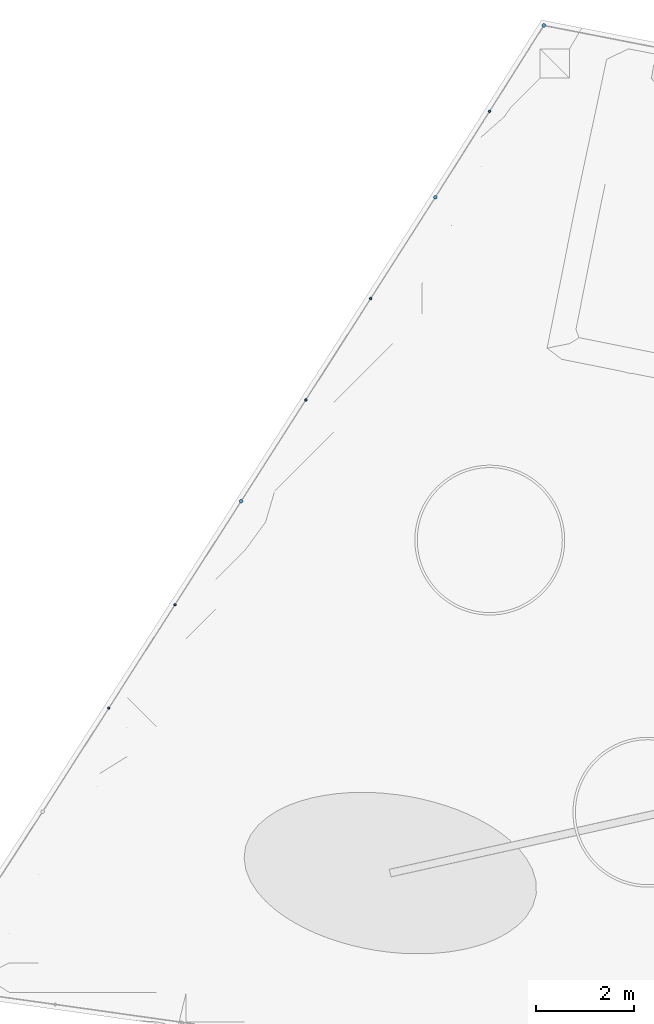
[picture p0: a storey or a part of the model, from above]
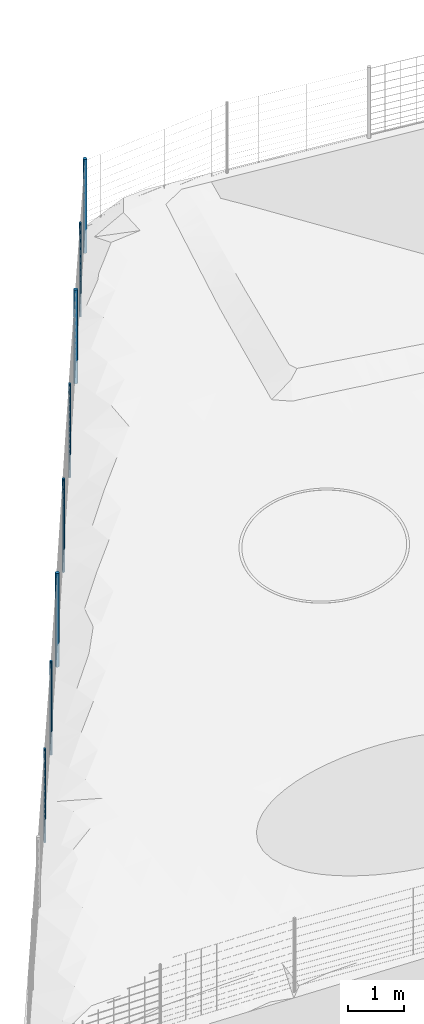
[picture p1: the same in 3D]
Properties of the parts of a building model (IFC4), part 3 of 3

# IfcPlate (158)
Name | In | PredefinedType | Material | Note | Product | NominalThickness_m | ModelledThickness_m | Status
Cobertura 7.16 | 01 · Jardim de inverno | SHEET | Policarbonato alveolar 16 mm · translúcido | 8 mm nominal glass; safety glazing and panel subdivision require specification. | Multiwall polycarbonate | 0.016 | 0.008 | Thickness, supplier and fixing system to confirm
Cobertura 8.16 | 01 · Jardim de inverno | SHEET | Policarbonato alveolar 16 mm · translúcido | 8 mm nominal glass; safety glazing and panel subdivision require specification. | Multiwall polycarbonate | 0.016 | 0.008 | Thickness, supplier and fixing system to confirm
Cobertura 1.17 | 01 · Jardim de inverno | SHEET | Policarbonato alveolar 16 mm · translúcido | 8 mm nominal glass; safety glazing and panel subdivision require specification. | Multiwall polycarbonate | 0.016 | 0.008 | Thickness, supplier and fixing system to confirm
Cobertura 2.17 | 01 · Jardim de inverno | SHEET | Policarbonato alveolar 16 mm · translúcido | 8 mm nominal glass; safety glazing and panel subdivision require specification. | Multiwall polycarbonate | 0.016 | 0.008 | Thickness, supplier and fixing system to confirm
Cobertura 3.17 | 01 · Jardim de inverno | SHEET | Policarbonato alveolar 16 mm · translúcido | 8 mm nominal glass; safety glazing and panel subdivision require specification. | Multiwall polycarbonate | 0.016 | 0.008 | Thickness, supplier and fixing system to confirm
Cobertura 4.17 | 01 · Jardim de inverno | SHEET | Policarbonato alveolar 16 mm · translúcido | 8 mm nominal glass; safety glazing and panel subdivision require specification. | Multiwall polycarbonate | 0.016 | 0.008 | Thickness, supplier and fixing system to confirm
Cobertura 5.17 | 01 · Jardim de inverno | SHEET | Policarbonato alveolar 16 mm · translúcido | 8 mm nominal glass; safety glazing and panel subdivision require specification. | Multiwall polycarbonate | 0.016 | 0.008 | Thickness, supplier and fixing system to confirm
Cobertura 6.17 | 01 · Jardim de inverno | SHEET | Policarbonato alveolar 16 mm · translúcido | 8 mm nominal glass; safety glazing and panel subdivision require specification. | Multiwall polycarbonate | 0.016 | 0.008 | Thickness, supplier and fixing system to confirm
Cobertura 7.17 | 01 · Jardim de inverno | SHEET | Policarbonato alveolar 16 mm · translúcido | 8 mm nominal glass; safety glazing and panel subdivision require specification. | Multiwall polycarbonate | 0.016 | 0.008 | Thickness, supplier and fixing system to confirm
Cobertura 8.17 | 01 · Jardim de inverno | SHEET | Policarbonato alveolar 16 mm · translúcido | 8 mm nominal glass; safety glazing and panel subdivision require specification. | Multiwall polycarbonate | 0.016 | 0.008 | Thickness, supplier and fixing system to confirm
2 x Empena da estufa | 01 · Jardim de inverno |  | Policarbonato alveolar 16 mm · translúcido |  | Multiwall polycarbonate | 0.016 | 0.008 | Thickness, supplier and fixing system to confirm
Cisterna · tampa estanque de inspeção | 00 · Habitação e estacionamento | SHEET | Aço galvanizado / Stahl verzinkt | Flush, closed 900 mm maintenance hatch; cover capacity and safe maintenance access to detail. Not a routine entrance.
4 x Pérgola · chapa de ancoragem | 00 · Habitação e estacionamento | SHEET | Aço galvanizado / Stahl verzinkt
9 x Projeção estufa · chapa de ancoragem | 00 · Habitação e estacionamento | SHEET | Aço galvanizado / Stahl verzinkt
2 x Contentor · chapa lateral | 00 · Habitação e estacionamento |  | Contentor · pintura 1
Contentor · chapa de fundo | 00 · Habitação e estacionamento |  | Contentor · pintura 1
2 x Contentor · chapa lateral | 00 · Habitação e estacionamento |  | Contentor · pintura 2
Contentor · chapa de fundo | 00 · Habitação e estacionamento |  | Contentor · pintura 2

# IfcRailing (23)
PredefinedType: GUARDRAIL; Material: Aço pintado / Stahl lackiert
Pset_CasaProvenance - DesignSource: Casa Sobreposta / configuration.json; ReferenceFile: 260617_CasaDFL_Estrutura_Terreno.ifc; ConstructionBasis: DESIGN_ASSUMPTION; Note: Study guard 1.10 m; twin handrails at 0.70 and 0.90 m on ramp; loads and fixings unverified.
Name | In
5 x Guarda perimetral da estufa | 01 · Jardim de inverno
Corrimão sala | 00 · Habitação e estacionamento
Corrimão garagem | 00 · Habitação e estacionamento
5 x Guarda do vazio | 01 · Jardim de inverno
Pódio · guarda sul | 00 · Habitação e estacionamento
Pódio · guarda poente sul | 00 · Habitação e estacionamento
Pódio · guarda poente norte | 00 · Habitação e estacionamento
Pódio · guarda norte | 00 · Habitação e estacionamento
2 x Jardim · corrimão poente | 00 · Habitação e estacionamento
2 x Jardim · guarda do patamar | 00 · Habitação e estacionamento
3 x Varanda · guarda | 00 · Habitação e estacionamento

# IfcRailing: SHEEP_WIRE_FENCE (82)
In: Lares · Rua das Mercês · artigo 4771
PredefinedType: USERDEFINED; Material: Aço galvanizado / Stahl verzinkt
Pset_CasaProvenance - DesignSource: Casa Sobreposta / configuration.json; ReferenceFile: 260617_CasaDFL_Estrutura_Terreno.ifc; ConstructionBasis: DESIGN_ASSUMPTION; Note: R10 concept geometry; dimensions and connections not structurally verified.
Pset_CasaFence - Height_m: 1.5; Mesh: Galvanised sheep netting, graduated line wires, 0.30 m vertical stays; Status: CONCEPT; wire gauge, tensioning and posts to specify
Name | PostSpacing_m
Vedação · rede ovelheira 1.001 | 2.31221
Vedação · rede ovelheira 1.002 | 2.31221
Vedação · rede ovelheira 1.003 | 2.31221
Vedação · rede ovelheira 1.004 | 2.85062
Vedação · rede ovelheira 1.005 | 2.85062
Vedação · rede ovelheira 1.006 | 2.85062
Vedação · rede ovelheira 1.007 | 2.85062
Vedação · rede ovelheira 1.008 | 2.41772
Vedação · rede ovelheira 1.009 | 2.41772
Vedação · rede ovelheira 1.010 | 2.41772
Vedação · rede ovelheira 1.011 | 2.41772
Vedação · rede ovelheira 1.012 | 2.41772
Vedação · rede ovelheira 1.013 | 2.4459
Vedação · rede ovelheira 1.014 | 2.4459
Vedação · rede ovelheira 1.015 | 2.4459
Vedação · rede ovelheira 1.016 | 2.4459
Vedação · rede ovelheira 1.017 | 2.4459
Vedação · rede ovelheira 1.018 | 2.41457
Vedação · rede ovelheira 1.019 | 2.41457
Vedação · rede ovelheira 1.020 | 2.41457
Vedação · rede ovelheira 1.021 | 2.41457
Vedação · rede ovelheira 1.022 | 2.41457
Vedação · rede ovelheira 1.023 | 2.93474
Vedação · rede ovelheira 1.024 | 2.93474
Vedação · rede ovelheira 1.025 | 2.93474
Vedação · rede ovelheira 1.026 | 2.93474
Vedação · rede ovelheira 1.027 | 2.4949
Vedação · rede ovelheira 1.028 | 2.4949
Vedação · rede ovelheira 1.029 | 2.4949
Vedação · rede ovelheira 1.030 | 2.4949
Vedação · rede ovelheira 1.031 | 2.4949
Vedação · rede ovelheira 1.032 | 2.41477
Vedação · rede ovelheira 1.033 | 2.41477
Vedação · rede ovelheira 1.034 | 2.41477
Vedação · rede ovelheira 1.035 | 2.41477
Vedação · rede ovelheira 1.036 | 2.90303
Vedação · rede ovelheira 1.037 | 2.90303
Vedação · rede ovelheira 1.038 | 2.59069
Vedação · rede ovelheira 1.039 | 2.59069
Vedação · rede ovelheira 1.040 | 2.59069
Vedação · rede ovelheira 1.041 | 2.12292
Vedação · rede ovelheira 1.042 | 2.12292
Vedação · rede ovelheira 1.043 | 2.49871
Vedação · rede ovelheira 1.044 | 2.49871
Vedação · rede ovelheira 1.045 | 2.49871
Vedação · rede ovelheira 1.046 | 2.44661
Vedação · rede ovelheira 1.047 | 2.44661
Vedação · rede ovelheira 1.048 | 2.44661
Vedação · rede ovelheira 1.049 | 2.06726
Vedação · rede ovelheira 1.050 | 2.06726
Vedação · rede ovelheira 1.051 | 2.68804
Vedação · rede ovelheira 1.052 | 2.68804
Vedação · rede ovelheira 1.053 | 2.76823
Vedação · rede ovelheira 1.054 | 2.76823
Vedação · rede ovelheira 1.055 | 2.76823
Vedação · rede ovelheira 1.056 | 2.73364
Vedação · rede ovelheira 1.057 | 2.73364
Vedação · rede ovelheira 1.058 | 2.73364
Vedação · rede ovelheira 1.059 | 2.9388
Vedação · rede ovelheira 1.060 | 2.9388
Vedação · rede ovelheira 1.061 | 2.99875
Vedação · rede ovelheira 1.062 | 2.99875
Vedação · rede ovelheira 1.063 | 2.99875
Vedação · rede ovelheira 1.064 | 2.42137
Vedação · rede ovelheira 1.065 | 2.42137
Vedação · rede ovelheira 1.066 | 2.42137
Vedação · rede ovelheira 1.067 | 2.42137
Vedação · rede ovelheira 1.068 | 2.65677
Vedação · rede ovelheira 1.069 | 2.65677
Vedação · rede ovelheira 1.070 | 2.65677
Vedação · rede ovelheira 1.071 | 2.65677
Vedação · rede ovelheira 1.072 | 2.96086
Vedação · rede ovelheira 1.073 | 2.96086
Vedação · rede ovelheira 1.074 | 2.96086
Vedação · rede ovelheira 1.075 | 2.83036
Vedação · rede ovelheira 1.076 | 2.83036
Vedação · rede ovelheira 1.077 | 2.83036
Vedação · rede ovelheira 1.078 | 2.61662
Vedação · rede ovelheira 1.079 | 2.61662
Vedação · rede ovelheira 1.080 | 2.61662
Vedação · rede ovelheira 1.081 | 2.61662
Vedação · rede ovelheira 1.082 | 1.96455

# IfcRoof, Cobertura translúcida da estufa
In: 01 · Jardim de inverno
PredefinedType: BARREL_ROOF; Material: Policarbonato alveolar 16 mm · translúcido
Pset_CasaProvenance - DesignSource: Casa Sobreposta / configuration.json; ReferenceFile: 260617_CasaDFL_Estrutura_Terreno.ifc; ConstructionBasis: DESIGN_ASSUMPTION; Note: Configurator Coutras section, scaled to 7.90 m with raised ridge; 8 mm glass and 35 mm ribs are study assumptions.
Pset_CasaPolycarbonate - Product: Multiwall polycarbonate; NominalThickness_m: 0.016; ModelledThickness_m: 0.008; Status: Thickness, supplier and fixing system to confirm

# IfcSanitaryTerminal (8)
Material: Cerâmica sanitária — esquema
Pset_CasaProvenance - DesignSource: Casa Sobreposta / configuration.json; ReferenceFile: 260617_CasaDFL_Estrutura_Terreno.ifc; ConstructionBasis: DESIGN_ASSUMPTION
Name | In | PredefinedType | Note
Banheira | 00 · Habitação e estacionamento | BATH | Schematic fixture, not a manufacturer object.
Lavatório 1 | 00 · Habitação e estacionamento | WASHHANDBASIN | Schematic fixture, not a manufacturer object.
Lavatório 2 | 00 · Habitação e estacionamento | WASHHANDBASIN | Schematic fixture, not a manufacturer object.
Sanita | 00 · Habitação e estacionamento | TOILETPAN | Schematic fixture, not a manufacturer object.
Bancada de cozinha | 00 · Habitação e estacionamento | TOILETPAN | Schematic fixture, not a manufacturer object.
Lavatório superior | 01 · Jardim de inverno | WASHHANDBASIN
Sanita superior | 01 · Jardim de inverno | TOILETPAN
Duche superior | 01 · Jardim de inverno | SHOWER

# IfcSlab (11)
Pset_CasaProvenance - DesignSource: Casa Sobreposta / configuration.json; ReferenceFile: 260617_CasaDFL_Estrutura_Terreno.ifc
Name | In | PredefinedType | Material | ConstructionBasis
OSB estrutural · 20 mm | 01 · Jardim de inverno | FLOOR | OSB | ADAPTED_REFERENCE | Pset_CasaProvenance - Note: Two real stair voids. Light protective finish assumed; drains and waterproof upstands require detailing.
Cisterna · laje de fundo 200 mm | -01 · Cisterna sob o terraço | BASESLAB | Betão armado / Stahlbeton | DESIGN_ASSUMPTION
Pódio · laje da casa 250 mm | 00 · Habitação e estacionamento | FLOOR | Betão armado / Stahlbeton | DESIGN_ASSUMPTION | Pset_CasaProvenance - Note: Suspended slab on discrete piers and grade beams. Natural slope retained where clear; local shallow excavation where beams meet rising ground. Sizes unverified.
Pódio · terraço e faixa de proteção sul | 00 · Habitação e estacionamento | FLOOR | Betão armado / Stahlbeton | DESIGN_ASSUMPTION | Pset_CasaProvenance - Note: Terrace 40 mm below house. West terrace over void/cistern; shallow local formation to east. Parking is a separate ground-supported pavement.
Estacionamento · pavimento apoiado no solo | 00 · Habitação e estacionamento | BASESLAB | Betão armado / Stahlbeton | DESIGN_ASSUMPTION | Pset_CasaProvenance - Note: R10 concept geometry; dimensions and connections not structurally verified.; Pset_CasaParking - GroundSupported: yes; LongitudinalGrade_percent: 2.5; Crossfall_percent: 4; HouseThresholdStep_m: 0.02; Status: Concept grading; pavement build-up and accessibility to detail
Jardim · patamar poente | 00 · Habitação e estacionamento | LANDING | Betão armado / Stahlbeton | DESIGN_ASSUMPTION
Varanda · faixa poente 1,20 m úteis | 01 · Jardim de inverno | FLOOR | Aço galvanizado / Stahl verzinkt | DESIGN_ASSUMPTION | Pset_CasaProvenance - Note: Open upper gallery; non-slip deck and member connections to design. 1.25 m gross strip, approximately 1.20 m clear.
2 x Contentor · piso ou teto | 00 · Habitação e estacionamento | FLOOR | Contentor · pintura 1 | DESIGN_ASSUMPTION
2 x Contentor · piso ou teto | 00 · Habitação e estacionamento | FLOOR | Contentor · pintura 2 | DESIGN_ASSUMPTION

# IfcStair (3)
In: 00 · Habitação e estacionamento
PredefinedType: STRAIGHT_RUN_STAIR
Pset_CasaProvenance - DesignSource: Casa Sobreposta / configuration.json; ReferenceFile: 260617_CasaDFL_Estrutura_Terreno.ifc
Name | ConstructionBasis | Note
Escada sala | ADAPTED_REFERENCE | Configurator 18 x 0.18 m risers / 17 x 0.265 m goings / 0.70 m width. Steel channels and OSB treads adapted from source.
Escada garagem | ADAPTED_REFERENCE | Configurator 18 x 0.18 m risers / 17 x 0.265 m goings / 0.70 m width. Steel channels and OSB treads adapted from source.
Jardim · escada pela fachada poente | DESIGN_ASSUMPTION | West-facing descent; no south opening. Survey-based concept.

# IfcStairFlight (3)
In: 00 · Habitação e estacionamento
PredefinedType: STRAIGHT
Pset_CasaProvenance - DesignSource: Casa Sobreposta / configuration.json; ReferenceFile: 260617_CasaDFL_Estrutura_Terreno.ifc
Name | NumberOfRisers | NumberOfTreads | RiserHeight (m) | TreadLength (m) | Material | ConstructionBasis
Lanço sala | 18 | 17 | 0.18 | 0.265 | OSB | ADAPTED_REFERENCE
Lanço garagem | 18 | 17 | 0.18 | 0.265 | OSB | ADAPTED_REFERENCE
Jardim · lanço poente | 12 | 11 | 0.159167 | 0.3 | Betão armado / Stahlbeton | DESIGN_ASSUMPTION

# IfcTank: RAINWATER_CISTERN, Cisterna · reservatório pluvial de estudo
In: -01 · Cisterna sob o terraço
PredefinedType: STORAGE
Pset_CasaProvenance - DesignSource: Casa Sobreposta / configuration.json; ReferenceFile: 260617_CasaDFL_Estrutura_Terreno.ifc; ConstructionBasis: DESIGN_ASSUMPTION; Note: Composite concrete vessel; provisional geometry only. No ordinary occupancy or stair access. Water depth and capacity to design.
Pset_CasaCistern - InternalPlanArea_m2: 17.8125; WaterDepthAssumed_m: 2; GeometricWaterVolume_m3: 35.625; SoffitClearanceAboveWater_m: 0.31; Status: Provisional water envelope; hydrostatic, uplift, watertightness, filtration, overflow and maintenance design pending

# IfcWall (17)
Pset_CasaProvenance - DesignSource: Casa Sobreposta / configuration.json; ReferenceFile: 260617_CasaDFL_Estrutura_Terreno.ifc; ConstructionBasis: ADAPTED_REFERENCE
Name | In | Material | OverallThickness_m | SourceModelSkinThicknesses_m | Core_m | Pset_CasaAssembly, Note
Divisória 1 · OSB 22 mm nas duas faces | 00 · Habitação e estacionamento | OSB, Lã mineral / Mineralwolle 2 | Pset_CasaProvenance - Note: Original centreline/door positions preserved; schematic footprint widened 20 mm per side. 22 mm OSB linings; mineral wool core; stud layout not developed.
Divisória 2 · OSB 22 mm nas duas faces | 00 · Habitação e estacionamento | OSB, Lã mineral / Mineralwolle 2 | Pset_CasaProvenance - Note: Original centreline/door positions preserved; schematic footprint widened 20 mm per side. 22 mm OSB linings; mineral wool core; stud layout not developed.
Divisória 3 · OSB 22 mm nas duas faces | 00 · Habitação e estacionamento | OSB, Lã mineral / Mineralwolle 2 | Pset_CasaProvenance - Note: Original centreline/door positions preserved; schematic footprint widened 20 mm per side. 22 mm OSB linings; mineral wool core; stud layout not developed.
Divisória 4 · OSB 22 mm nas duas faces | 00 · Habitação e estacionamento | OSB, Lã mineral / Mineralwolle 2 | Pset_CasaProvenance - Note: Original centreline/door positions preserved; schematic footprint widened 20 mm per side. 22 mm OSB linings; mineral wool core; stud layout not developed.
Fachada norte · sandwich Casa DFL | 00 · Habitação e estacionamento | Aço pintado / Stahl lackiert 0.005 m, Lã mineral / Mineralwolle 2 0.12 m, Aço pintado / Stahl lackiert 0.00516 m | 0.13016 | 0.005 / 0.00516 | 0.12 | Source geometry retained; commercial sheet specification not established.
Separação do estacionamento | 00 · Habitação e estacionamento | Aço pintado / Stahl lackiert 0.005 m, Lã mineral / Mineralwolle 2 0.12 m, Aço pintado / Stahl lackiert 0.00516 m | 0.13016 | 0.005 / 0.00516 | 0.12 | Source geometry retained; commercial sheet specification not established.
Painel opaco sul 0 | 00 · Habitação e estacionamento | Aço pintado / Stahl lackiert 0.005 m, Lã mineral / Mineralwolle 2 0.12 m, Aço pintado / Stahl lackiert 0.00516 m | 0.13016 | 0.005 / 0.00516 | 0.12 | Source geometry retained; commercial sheet specification not established.
Painel opaco sul 1 | 00 · Habitação e estacionamento | Aço pintado / Stahl lackiert 0.005 m, Lã mineral / Mineralwolle 2 0.12 m, Aço pintado / Stahl lackiert 0.00516 m | 0.13016 | 0.005 / 0.00516 | 0.12 | Source geometry retained; commercial sheet specification not established.
Painel opaco sul 3 | 00 · Habitação e estacionamento | Aço pintado / Stahl lackiert 0.005 m, Lã mineral / Mineralwolle 2 0.12 m, Aço pintado / Stahl lackiert 0.00516 m | 0.13016 | 0.005 / 0.00516 | 0.12 | Source geometry retained; commercial sheet specification not established.
Painel opaco sul 5 | 00 · Habitação e estacionamento | Aço pintado / Stahl lackiert 0.005 m, Lã mineral / Mineralwolle 2 0.12 m, Aço pintado / Stahl lackiert 0.00516 m | 0.13016 | 0.005 / 0.00516 | 0.12 | Source geometry retained; commercial sheet specification not established.
Painel opaco sul 7 | 00 · Habitação e estacionamento | Aço pintado / Stahl lackiert 0.005 m, Lã mineral / Mineralwolle 2 0.12 m, Aço pintado / Stahl lackiert 0.00516 m | 0.13016 | 0.005 / 0.00516 | 0.12 | Source geometry retained; commercial sheet specification not established.
Painel opaco sul 9 | 00 · Habitação e estacionamento | Aço pintado / Stahl lackiert 0.005 m, Lã mineral / Mineralwolle 2 0.12 m, Aço pintado / Stahl lackiert 0.00516 m | 0.13016 | 0.005 / 0.00516 | 0.12 | Source geometry retained; commercial sheet specification not established.
Painel opaco sul 11 | 00 · Habitação e estacionamento | Aço pintado / Stahl lackiert 0.005 m, Lã mineral / Mineralwolle 2 0.12 m, Aço pintado / Stahl lackiert 0.00516 m | 0.13016 | 0.005 / 0.00516 | 0.12 | Source geometry retained; commercial sheet specification not established.
Banho superior · poente | 01 · Jardim de inverno | OSB
Banho superior · norte | 01 · Jardim de inverno | OSB
Banho superior · nascente | 01 · Jardim de inverno | OSB
Banho superior · sul | 01 · Jardim de inverno | OSB

# IfcWall: Cisterna · parede nascente
In: -01 · Cisterna sob o terraço
PredefinedType: USERDEFINED; Material: Betão armado / Stahlbeton
Pset_CasaProvenance - DesignSource: Casa Sobreposta / configuration.json; ReferenceFile: 260617_CasaDFL_Estrutura_Terreno.ifc; ConstructionBasis: DESIGN_ASSUMPTION; Note: 250 mm RC study wall, waterproofing and joints to detail; no retaining capacity asserted.

# IfcWall: Cisterna · parede norte
In: -01 · Cisterna sob o terraço
PredefinedType: USERDEFINED; Material: Betão armado / Stahlbeton
Pset_CasaProvenance - DesignSource: Casa Sobreposta / configuration.json; ReferenceFile: 260617_CasaDFL_Estrutura_Terreno.ifc; ConstructionBasis: DESIGN_ASSUMPTION; Note: 250 mm RC study wall, waterproofing and joints to detail; no retaining capacity asserted.

# IfcWall: Cisterna · parede poente
In: -01 · Cisterna sob o terraço
PredefinedType: USERDEFINED; Material: Betão armado / Stahlbeton
Pset_CasaProvenance - DesignSource: Casa Sobreposta / configuration.json; ReferenceFile: 260617_CasaDFL_Estrutura_Terreno.ifc; ConstructionBasis: DESIGN_ASSUMPTION; Note: 250 mm RC study wall, waterproofing and joints to detail; no retaining capacity asserted.

# IfcWall: Cisterna · parede sul
In: -01 · Cisterna sob o terraço
PredefinedType: USERDEFINED; Material: Betão armado / Stahlbeton
Pset_CasaProvenance - DesignSource: Casa Sobreposta / configuration.json; ReferenceFile: 260617_CasaDFL_Estrutura_Terreno.ifc; ConstructionBasis: DESIGN_ASSUMPTION; Note: 250 mm RC study wall, waterproofing and joints to detail; no retaining capacity asserted.

# IfcWindow (58)
PredefinedType: WINDOW; PartitioningType: SINGLE_PANEL
Pset_CasaProvenance - DesignSource: Casa Sobreposta / configuration.json; ReferenceFile: 260617_CasaDFL_Estrutura_Terreno.ifc; ConstructionBasis: DESIGN_ASSUMPTION
Name | In | OverallHeight (m) | OverallWidth (m) | Material | Product | NominalThickness_m | ModelledThickness_m | Status
Rasgo norte 1 | 00 · Habitação e estacionamento | 0.3 | 3.79 | Vidro / Normalglas
Rasgo norte 2 | 00 · Habitação e estacionamento | 0.3 | 3.79 | Vidro / Normalglas
Rasgo norte 3 | 00 · Habitação e estacionamento | 0.3 | 3.79 | Vidro / Normalglas
Rasgo norte 4 | 00 · Habitação e estacionamento | 0.3 | 3.79 | Vidro / Normalglas
Rasgo norte 5 | 00 · Habitação e estacionamento | 0.3 | 3.79 | Vidro / Normalglas
Rasgo norte 6 | 00 · Habitação e estacionamento | 0.3 | 3.79 | Vidro / Normalglas
Rasgo norte 7 | 00 · Habitação e estacionamento | 0.3 | 0.71 | Vidro / Normalglas
Fachada poente integralmente envidraçada · módulo 1 | 00 · Habitação e estacionamento | 2.918 | 1.55 | Vidro / Normalglas | Pset_CasaGlazedFacade - Revision: R02 · kiwi pergola; Facade: WEST / highlighted end in user sketch; Infill: Full-height glazing; no opaque infill; GlazingSpecification: 8 mm nominal representation only; insulated safety glazing assembly to specify
Fachada poente integralmente envidraçada · módulo 2 | 00 · Habitação e estacionamento | 2.918 | 1.55 | Vidro / Normalglas | Pset_CasaGlazedFacade - Revision: R02 · kiwi pergola; Facade: WEST / highlighted end in user sketch; Infill: Full-height glazing; no opaque infill; GlazingSpecification: 8 mm nominal representation only; insulated safety glazing assembly to specify
Fachada poente integralmente envidraçada · módulo 3 | 00 · Habitação e estacionamento | 2.918 | 1.55 | Vidro / Normalglas | Pset_CasaGlazedFacade - Revision: R02 · kiwi pergola; Facade: WEST / highlighted end in user sketch; Infill: Full-height glazing; no opaque infill; GlazingSpecification: 8 mm nominal representation only; insulated safety glazing assembly to specify
Estufa sul 1 | 01 · Jardim de inverno | 2.43 | 1.95 | Policarbonato alveolar 16 mm · translúcido | Multiwall polycarbonate | 0.016 | 0.008 | Thickness, supplier and fixing system to confirm
Estufa sul 2 | 01 · Jardim de inverno | 2.43 | 1.95 | Policarbonato alveolar 16 mm · translúcido | Multiwall polycarbonate | 0.016 | 0.008 | Thickness, supplier and fixing system to confirm
Estufa sul 3 | 01 · Jardim de inverno | 2.43 | 1.95 | Policarbonato alveolar 16 mm · translúcido | Multiwall polycarbonate | 0.016 | 0.008 | Thickness, supplier and fixing system to confirm
Estufa sul 4 | 01 · Jardim de inverno | 2.43 | 1.95 | Policarbonato alveolar 16 mm · translúcido | Multiwall polycarbonate | 0.016 | 0.008 | Thickness, supplier and fixing system to confirm
Estufa sul 5 | 01 · Jardim de inverno | 2.43 | 1.95 | Policarbonato alveolar 16 mm · translúcido | Multiwall polycarbonate | 0.016 | 0.008 | Thickness, supplier and fixing system to confirm
Estufa sul 6 | 01 · Jardim de inverno | 2.43 | 1.95 | Policarbonato alveolar 16 mm · translúcido | Multiwall polycarbonate | 0.016 | 0.008 | Thickness, supplier and fixing system to confirm
Estufa sul 7 | 01 · Jardim de inverno | 2.43 | 1.95 | Policarbonato alveolar 16 mm · translúcido | Multiwall polycarbonate | 0.016 | 0.008 | Thickness, supplier and fixing system to confirm
Estufa sul 8 | 01 · Jardim de inverno | 2.43 | 1.95 | Policarbonato alveolar 16 mm · translúcido | Multiwall polycarbonate | 0.016 | 0.008 | Thickness, supplier and fixing system to confirm
Estufa sul 9 | 01 · Jardim de inverno | 2.43 | 1.95 | Policarbonato alveolar 16 mm · translúcido | Multiwall polycarbonate | 0.016 | 0.008 | Thickness, supplier and fixing system to confirm
Estufa sul 10 | 01 · Jardim de inverno | 2.43 | 1.95 | Policarbonato alveolar 16 mm · translúcido | Multiwall polycarbonate | 0.016 | 0.008 | Thickness, supplier and fixing system to confirm
Estufa sul 11 | 01 · Jardim de inverno | 2.43 | 1.95 | Policarbonato alveolar 16 mm · translúcido | Multiwall polycarbonate | 0.016 | 0.008 | Thickness, supplier and fixing system to confirm
Estufa sul 12 | 01 · Jardim de inverno | 2.43 | 1.95 | Policarbonato alveolar 16 mm · translúcido | Multiwall polycarbonate | 0.016 | 0.008 | Thickness, supplier and fixing system to confirm
Estufa sul 13 | 01 · Jardim de inverno | 2.43 | 1.95 | Policarbonato alveolar 16 mm · translúcido | Multiwall polycarbonate | 0.016 | 0.008 | Thickness, supplier and fixing system to confirm
Estufa sul 14 | 01 · Jardim de inverno | 2.43 | 1.95 | Policarbonato alveolar 16 mm · translúcido | Multiwall polycarbonate | 0.016 | 0.008 | Thickness, supplier and fixing system to confirm
Estufa sul 15 | 01 · Jardim de inverno | 2.43 | 1.95 | Policarbonato alveolar 16 mm · translúcido | Multiwall polycarbonate | 0.016 | 0.008 | Thickness, supplier and fixing system to confirm
Estufa sul 16 | 01 · Jardim de inverno | 2.43 | 1.95 | Policarbonato alveolar 16 mm · translúcido | Multiwall polycarbonate | 0.016 | 0.008 | Thickness, supplier and fixing system to confirm
Estufa norte 1 | 01 · Jardim de inverno | 2.43 | 1.95 | Policarbonato alveolar 16 mm · translúcido | Multiwall polycarbonate | 0.016 | 0.008 | Thickness, supplier and fixing system to confirm
Estufa norte 2 | 01 · Jardim de inverno | 2.43 | 1.95 | Policarbonato alveolar 16 mm · translúcido | Multiwall polycarbonate | 0.016 | 0.008 | Thickness, supplier and fixing system to confirm
Estufa norte 3 | 01 · Jardim de inverno | 2.43 | 1.95 | Policarbonato alveolar 16 mm · translúcido | Multiwall polycarbonate | 0.016 | 0.008 | Thickness, supplier and fixing system to confirm
Estufa norte 4 | 01 · Jardim de inverno | 2.43 | 1.95 | Policarbonato alveolar 16 mm · translúcido | Multiwall polycarbonate | 0.016 | 0.008 | Thickness, supplier and fixing system to confirm
Estufa norte 5 | 01 · Jardim de inverno | 2.43 | 1.95 | Policarbonato alveolar 16 mm · translúcido | Multiwall polycarbonate | 0.016 | 0.008 | Thickness, supplier and fixing system to confirm
Estufa norte 6 | 01 · Jardim de inverno | 2.43 | 1.95 | Policarbonato alveolar 16 mm · translúcido | Multiwall polycarbonate | 0.016 | 0.008 | Thickness, supplier and fixing system to confirm
Estufa norte 7 | 01 · Jardim de inverno | 2.43 | 1.95 | Policarbonato alveolar 16 mm · translúcido | Multiwall polycarbonate | 0.016 | 0.008 | Thickness, supplier and fixing system to confirm
Estufa norte 8 | 01 · Jardim de inverno | 2.43 | 1.95 | Policarbonato alveolar 16 mm · translúcido | Multiwall polycarbonate | 0.016 | 0.008 | Thickness, supplier and fixing system to confirm
Estufa norte 9 | 01 · Jardim de inverno | 2.43 | 1.95 | Policarbonato alveolar 16 mm · translúcido | Multiwall polycarbonate | 0.016 | 0.008 | Thickness, supplier and fixing system to confirm
Estufa norte 10 | 01 · Jardim de inverno | 2.43 | 1.95 | Policarbonato alveolar 16 mm · translúcido | Multiwall polycarbonate | 0.016 | 0.008 | Thickness, supplier and fixing system to confirm
Estufa norte 11 | 01 · Jardim de inverno | 2.43 | 1.95 | Policarbonato alveolar 16 mm · translúcido | Multiwall polycarbonate | 0.016 | 0.008 | Thickness, supplier and fixing system to confirm
Estufa norte 12 | 01 · Jardim de inverno | 2.43 | 1.95 | Policarbonato alveolar 16 mm · translúcido | Multiwall polycarbonate | 0.016 | 0.008 | Thickness, supplier and fixing system to confirm
Estufa norte 13 | 01 · Jardim de inverno | 2.43 | 1.95 | Policarbonato alveolar 16 mm · translúcido | Multiwall polycarbonate | 0.016 | 0.008 | Thickness, supplier and fixing system to confirm
Estufa norte 14 | 01 · Jardim de inverno | 2.43 | 1.95 | Policarbonato alveolar 16 mm · translúcido | Multiwall polycarbonate | 0.016 | 0.008 | Thickness, supplier and fixing system to confirm
Estufa norte 15 | 01 · Jardim de inverno | 2.43 | 1.95 | Policarbonato alveolar 16 mm · translúcido | Multiwall polycarbonate | 0.016 | 0.008 | Thickness, supplier and fixing system to confirm
Estufa norte 16 | 01 · Jardim de inverno | 2.43 | 1.95 | Policarbonato alveolar 16 mm · translúcido | Multiwall polycarbonate | 0.016 | 0.008 | Thickness, supplier and fixing system to confirm
Varanda · bandeira da porta | 01 · Jardim de inverno | 0.73 | 1.05 | Policarbonato alveolar 16 mm · translúcido | Multiwall polycarbonate | 0.016 | 0.008 | Thickness, supplier and fixing system to confirm
Varanda · vidro lateral | 01 · Jardim de inverno | 2.93 | 0.1 | Policarbonato alveolar 16 mm · translúcido | Multiwall polycarbonate | 0.016 | 0.008 | Thickness, supplier and fixing system to confirm
Varanda · vidro lateral | 01 · Jardim de inverno | 2.93 | 0.675 | Policarbonato alveolar 16 mm · translúcido | Multiwall polycarbonate | 0.016 | 0.008 | Thickness, supplier and fixing system to confirm
Estufa poente 2 | 01 · Jardim de inverno | 2.93 | 1.925 | Policarbonato alveolar 16 mm · translúcido | Multiwall polycarbonate | 0.016 | 0.008 | Thickness, supplier and fixing system to confirm
Estufa poente 3 | 01 · Jardim de inverno | 2.93 | 1.925 | Policarbonato alveolar 16 mm · translúcido | Multiwall polycarbonate | 0.016 | 0.008 | Thickness, supplier and fixing system to confirm
Estufa poente 4 | 01 · Jardim de inverno | 2.93 | 1.925 | Policarbonato alveolar 16 mm · translúcido | Multiwall polycarbonate | 0.016 | 0.008 | Thickness, supplier and fixing system to confirm
Estufa nascente 1 | 01 · Jardim de inverno | 2.93 | 1.925 | Policarbonato alveolar 16 mm · translúcido | Multiwall polycarbonate | 0.016 | 0.008 | Thickness, supplier and fixing system to confirm
Estufa nascente 2 | 01 · Jardim de inverno | 2.93 | 1.925 | Policarbonato alveolar 16 mm · translúcido | Multiwall polycarbonate | 0.016 | 0.008 | Thickness, supplier and fixing system to confirm
Estufa nascente 3 | 01 · Jardim de inverno | 2.93 | 1.925 | Policarbonato alveolar 16 mm · translúcido | Multiwall polycarbonate | 0.016 | 0.008 | Thickness, supplier and fixing system to confirm
Estufa nascente 4 | 01 · Jardim de inverno | 2.93 | 1.925 | Policarbonato alveolar 16 mm · translúcido | Multiwall polycarbonate | 0.016 | 0.008 | Thickness, supplier and fixing system to confirm
Caixa térmica 1 · west | 01 · Jardim de inverno | 2.15 | 4.7 | Vidro / Normalglas
Caixa térmica 1 · east | 01 · Jardim de inverno | 2.15 | 4.7 | Vidro / Normalglas
Caixa térmica 1 · south | 01 · Jardim de inverno | 2.15 | 0.9 | Vidro / Normalglas
Caixa térmica 2 · west | 01 · Jardim de inverno | 2.15 | 4.7 | Vidro / Normalglas
Caixa térmica 2 · east | 01 · Jardim de inverno | 2.15 | 4.7 | Vidro / Normalglas
Caixa térmica 2 · north | 01 · Jardim de inverno | 2.15 | 0.91 | Vidro / Normalglas
